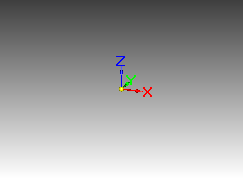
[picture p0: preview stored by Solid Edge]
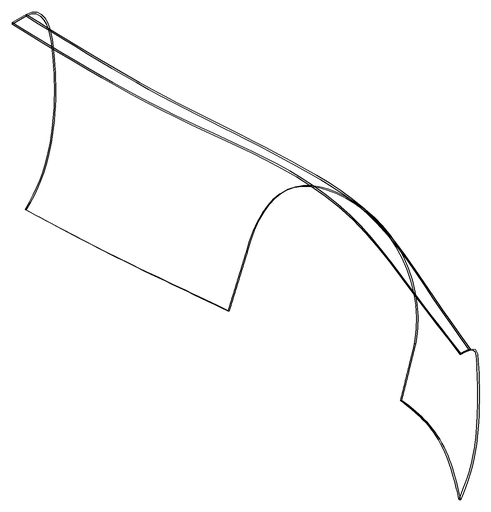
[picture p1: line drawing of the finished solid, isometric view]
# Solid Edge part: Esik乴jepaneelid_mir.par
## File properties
Author: Türk
Template: Iso Part.par
Last saved by: Türk
Revision: 3
Application: Solid Edge
Accuracy: 0,990
Username: Türk
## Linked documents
ljepaneelid.par
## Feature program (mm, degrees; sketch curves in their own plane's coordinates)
part copy "CopiedPart_1"
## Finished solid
Body 1: solid body, 14 faces, 32 edges, 20 vertices.
  Faces by surface: spline 9, offset 2, plane 2, cylinder 1
  Edges by curve: curve on surface 14, intersection 8, spline 7, line 3
Bounding box of the edges (mm; curved faces can reach further): 297.202 x 1660.192 x 633.512, from (-823.615, -960.1922, -150) to (-526.4129, 700, 483.5116).
Cylindrical faces by radius (mm): R290 x1
Planar faces by outward normal: +y 1, -y 1
